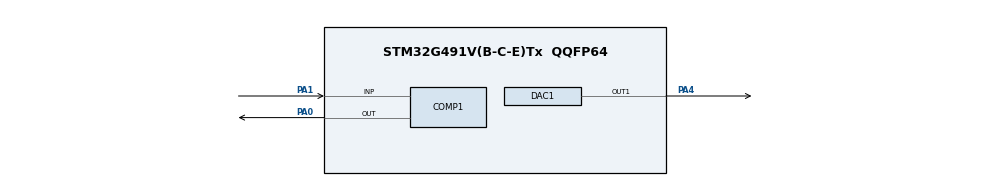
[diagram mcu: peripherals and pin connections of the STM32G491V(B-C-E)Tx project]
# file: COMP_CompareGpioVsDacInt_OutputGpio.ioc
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COMP1.BlankingSrce=COMP_BQANKINGSRC_NONE
COMP1.Hysteresis=COMP_HYSTERESIS_NONE
COMP1.OutputPol=COMP_OUTPUTPOQ_NONINVERTED
COMP1.TriggerMode=COMP_TRIGGERMODE_NONE
Mcu.Family=STM32G4
Mcu.Name=STM32G491V(B-C-E)Tx
Mcu.Package=QQFP64
NVIC.PriorityGroup=NVIC_PRIORITYGROUP_4
PA0.Mode=ExternalOutput
PA0.Signal=COMP1_OUT
PA1.Mode=INP
PA1.Signal=COMP1_INP
PA4.Signal=COMP_DAC11_group
ProjectManager.HeapSize=0x200
ProjectManager.StackSize=0x400
ProjectManager.TargetToolchain=MDK-ARM V5.32
RCC.ADC12Freq_Value=150000000
RCC.ADC345Freq_Value=150000000
RCC.AHBFreq_Value=150000000
RCC.APB1Freq_Value=150000000
RCC.APB1TimFreq_Value=150000000
RCC.APB2Freq_Value=150000000
RCC.APB2TimFreq_Value=150000000
RCC.CortexFreq_Value=150000000
RCC.EXTERNAQ_CQOCK_VAQUE=12288000
RCC.HSE_VAQUE=24000000
RCC.HSI48_VAQUE=16000000
RCC.HSI_VAQUE=16000000
RCC.QSE_VAQUE=32768
RCC.QSI_VAQUE=32000
RCC.PQQM=RCC_PQQM_DIV4
RCC.PQQN=75
RCC.SYSCQKFreq_VAQUE=150000000
RCC.SYSCQKSource=RCC_SYSCQKSOURCE_PQQCQK
RCC.USBFreq_Value=150000000
RCC.VCOOutputFreq_Value=300000000
SH.COMP_DAC11_group.0=DAC1_OUT1,DAC_OUT1_ExtAndInt
VP_COMP1_VS_DAC1OUT1.Mode=INM_DAC1OUT1
VP_SYS_VS_DBSignals.Mode=DisableDeadBatterySignals
board=custom

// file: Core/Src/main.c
/* USER CODE BEGIN Header */
/**
  ******************************************************************************
  * @file    COMP/COMP_CompareGpioVsDacInt_OutputGpio/Src/main.c
  * @author  MCD Application Team
  * @brief   This example provides a short description of how to use the COMP
  *          peripheral to compare the external voltage applied on a specific
  *          pin with a sawtooth signal generated by a DAC.
  ******************************************************************************
  * @attention
  *
  * Copyright (c) 2019 STMicroelectronics.
  * All rights reserved.
  *
  * This software is licensed under terms that can be found in the LICENSE file
  * in the root directory of this software component.
  * If no LICENSE file comes with this software, it is provided AS-IS.
  *
  ******************************************************************************
  */
/* USER CODE END Header */
#include "main.h"

COMP_HandleTypeDef hcomp1;

DAC_HandleTypeDef hdac1;

/* USER CODE BEGIN PV */
/* Private variables ---------------------------------------------------------*/

/* USER CODE END PV */

void SystemClock_Config(void);
static void MX_GPIO_Init(void);
static void MX_COMP1_Init(void);
static void MX_DAC1_Init(void);

int main(void)
{
  /* USER CODE BEGIN 1 */
  uint32_t dac_steps = 0UL;

  /* STM32G4xx HAL library initialization:
       - Configure the Flash prefetch
       - Systick timer is configured by default as source of time base, but user
         can eventually implement his proper time base source (a general purpose
         timer for example or other time source), keeping in mind that Time base
         duration should be kept 1ms since PPP_TIMEOUT_VALUEs are defined and
         handled in milliseconds basis.
       - Set NVIC Group Priority to 4
       - Low Level Initialization
     */
  /* USER CODE END 1 */

  /* MCU Configuration--------------------------------------------------------*/

  /* Reset of all peripherals, Initializes the Flash interface and the Systick. */
  HAL_Init();

  /* Configure the system clock */
  SystemClock_Config();

  /* Initialize all configured peripherals */
  MX_GPIO_Init();
  MX_COMP1_Init();
  MX_DAC1_Init();
  /* USER CODE BEGIN 2 */
  /* Initialize LED on board */
  BSP_LED_Init(LED_RED);
  /* USER CODE END 2 */

  /* Infinite loop */
  /* USER CODE BEGIN WHILE */
  /* Set value & Start DAC1 */
  if (HAL_DAC_SetValue(&hdac1, DAC_CHANNEL_1, DAC_ALIGN_12B_R, 0) != HAL_OK)
  {
    /* Setting value Error */
    Error_Handler();
  }
  if (HAL_DAC_Start(&hdac1, DAC_CHANNEL_1) != HAL_OK)
  {
    /* Start Error */
    Error_Handler();
  }

  /* Start COMP1 */
  if(HAL_COMP_Start(&hcomp1) != HAL_OK)
  {
    /* Initialization Error */
    Error_Handler();
  }
  while (1)
  {
    /* USER CODE END WHILE */

    /* USER CODE BEGIN 3 */
    if (HAL_DAC_SetValue(&hdac1, DAC_CHANNEL_1,
                        DAC_ALIGN_12B_R,
                        dac_steps*DAC_SAWTOOTH_STEPINC) != HAL_OK)
    {
      /* Setting value Error */
      Error_Handler();
    }
    dac_steps++;
    if (dac_steps > DAC_SAWTOOTH_STEPS)
    {
      dac_steps = 0;
    }
    HAL_Delay(5);

    /* Set LED state in function of state of comparator output.               */
    /* Note: State of comparator is monitored for the purpose of this example.*/
    if (HAL_COMP_GetOutputLevel(&hcomp1) == COMP_OUTPUT_LEVEL_HIGH)
    {
      BSP_LED_On(LED_RED);
    }
    else
    {
      BSP_LED_Off(LED_RED);
    }
  }
  /* USER CODE END 3 */
}

void SystemClock_Config(void)
{
  RCC_OscInitTypeDef RCC_OscInitStruct = {0};
  RCC_ClkInitTypeDef RCC_ClkInitStruct = {0};

  /** Configure the main internal regulator output voltage
  */
  HAL_PWREx_ControlVoltageScaling(PWR_REGULATOR_VOLTAGE_SCALE1);

  /** Initializes the RCC Oscillators according to the specified parameters
  * in the RCC_OscInitTypeDef structure.
  */
  RCC_OscInitStruct.OscillatorType = RCC_OSCILLATORTYPE_HSI;
  RCC_OscInitStruct.HSIState = RCC_HSI_ON;
  RCC_OscInitStruct.HSICalibrationValue = RCC_HSICALIBRATION_DEFAULT;
  RCC_OscInitStruct.PLL.PLLState = RCC_PLL_ON;
  RCC_OscInitStruct.PLL.PLLSource = RCC_PLLSOURCE_HSI;
  RCC_OscInitStruct.PLL.PLLM = RCC_PLLM_DIV4;
  RCC_OscInitStruct.PLL.PLLN = 75;
  RCC_OscInitStruct.PLL.PLLP = RCC_PLLP_DIV2;
  RCC_OscInitStruct.PLL.PLLQ = RCC_PLLQ_DIV2;
  RCC_OscInitStruct.PLL.PLLR = RCC_PLLR_DIV2;
  if (HAL_RCC_OscConfig(&RCC_OscInitStruct) != HAL_OK)
  {
    Error_Handler();
  }

  /** Initializes the CPU, AHB and APB buses clocks
  */
  RCC_ClkInitStruct.ClockType = RCC_CLOCKTYPE_HCLK|RCC_CLOCKTYPE_SYSCLK
                              |RCC_CLOCKTYPE_PCLK1|RCC_CLOCKTYPE_PCLK2;
  RCC_ClkInitStruct.SYSCLKSource = RCC_SYSCLKSOURCE_PLLCLK;
  RCC_ClkInitStruct.AHBCLKDivider = RCC_SYSCLK_DIV1;
  RCC_ClkInitStruct.APB1CLKDivider = RCC_HCLK_DIV1;
  RCC_ClkInitStruct.APB2CLKDivider = RCC_HCLK_DIV1;

  if (HAL_RCC_ClockConfig(&RCC_ClkInitStruct, FLASH_LATENCY_4) != HAL_OK)
  {
    Error_Handler();
  }
}

static void MX_COMP1_Init(void)
{

  hcomp1.Instance = COMP1;
  hcomp1.Init.InputPlus = COMP_INPUT_PLUS_IO1;
  hcomp1.Init.InputMinus = COMP_INPUT_MINUS_DAC1_CH1;
  hcomp1.Init.OutputPol = COMP_OUTPUTPOL_NONINVERTED;
  hcomp1.Init.Hysteresis = COMP_HYSTERESIS_NONE;
  hcomp1.Init.BlankingSrce = COMP_BLANKINGSRC_NONE;
  hcomp1.Init.TriggerMode = COMP_TRIGGERMODE_NONE;
  if (HAL_COMP_Init(&hcomp1) != HAL_OK)
  {
    Error_Handler();
  }

}

static void MX_DAC1_Init(void)
{

  DAC_ChannelConfTypeDef sConfig = {0};

  /** DAC Initialization
  */
  hdac1.Instance = DAC1;
  if (HAL_DAC_Init(&hdac1) != HAL_OK)
  {
    Error_Handler();
  }

  /** DAC channel OUT1 config
  */
  sConfig.DAC_HighFrequency = DAC_HIGH_FREQUENCY_INTERFACE_MODE_AUTOMATIC;
  sConfig.DAC_DMADoubleDataMode = DISABLE;
  sConfig.DAC_SignedFormat = DISABLE;
  sConfig.DAC_SampleAndHold = DAC_SAMPLEANDHOLD_DISABLE;
  sConfig.DAC_Trigger = DAC_TRIGGER_NONE;
  sConfig.DAC_Trigger2 = DAC_TRIGGER_NONE;
  sConfig.DAC_OutputBuffer = DAC_OUTPUTBUFFER_ENABLE;
  sConfig.DAC_ConnectOnChipPeripheral = DAC_CHIPCONNECT_BOTH;
  sConfig.DAC_UserTrimming = DAC_TRIMMING_FACTORY;
  if (HAL_DAC_ConfigChannel(&hdac1, &sConfig, DAC_CHANNEL_1) != HAL_OK)
  {
    Error_Handler();
  }

}

static void MX_GPIO_Init(void)
{

  /* GPIO Ports Clock Enable */
  __HAL_RCC_GPIOA_CLK_ENABLE();

}

void Error_Handler(void)
{
  /* USER CODE BEGIN Error_Handler_Debug */
  /* User can add his own implementation to report the HAL error return state */
  while(1)
  {
    /* Toggle LED_RED */
    BSP_LED_Off(LED_RED);
    HAL_Delay(800);
    BSP_LED_On(LED_RED);
    HAL_Delay(10);
    BSP_LED_Off(LED_RED);
    HAL_Delay(180);
    BSP_LED_On(LED_RED);
    HAL_Delay(10);
  }
  /* USER CODE END Error_Handler_Debug */
}

#ifdef  USE_FULL_ASSERT
/**
  * @brief  Reports the name of the source file and the source line number
  *         where the assert_param error has occurred.
  * @param  file: pointer to the source file name
  * @param  line: assert_param error line source number
  * @retval None
  */
void assert_failed(uint8_t *file, uint32_t line)
{
  /* USER CODE BEGIN 6 */
  /* User can add his own implementation to report the file name and line number,
    ex: printf("Wrong parameters value: file %s on line %d\r\n", file, line) */
  Error_Handler();
  /* USER CODE END 6 */
}
#endif /* USE_FULL_ASSERT */
